VERSION 5.7 ;
  NOWIREEXTENSIONATPIN ON ;
  DIVIDERCHAR "/" ;
  BUSBITCHARS "[]" ;
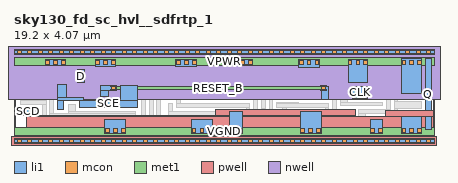
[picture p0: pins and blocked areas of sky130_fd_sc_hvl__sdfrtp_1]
MACRO sky130_fd_sc_hvl__sdfrtp_1
  CLASS BLOCK ;
  FOREIGN sky130_fd_sc_hvl__sdfrtp_1 ;
  ORIGIN 0.000 0.000 ;
  SIZE 19.200 BY 4.070 ;
  PIN CLK
    ANTENNAGATEAREA 0.585000 ;
    PORT
      LAYER li1 ;
        RECT 15.485 1.955 16.140 2.495 ;
    END
  END CLK
  PIN D
    ANTENNAGATEAREA 0.420000 ;
    PORT
      LAYER li1 ;
        RECT 2.910 2.660 3.205 3.260 ;
    END
  END D
  PIN RESET_B
    ANTENNAGATEAREA 1.260000 ;
    PORT
      LAYER li1 ;
        RECT 3.965 2.290 4.675 2.525 ;
        RECT 3.965 2.015 4.300 2.290 ;
        RECT 8.295 2.225 8.760 2.535 ;
        RECT 14.040 1.895 14.370 2.490 ;
      LAYER mcon ;
        RECT 4.475 2.320 4.645 2.490 ;
        RECT 8.315 2.320 8.485 2.490 ;
        RECT 14.075 2.320 14.245 2.490 ;
      LAYER met1 ;
        RECT 4.415 2.475 4.705 2.520 ;
        RECT 8.255 2.475 8.545 2.520 ;
        RECT 14.015 2.475 14.305 2.520 ;
        RECT 4.415 2.335 14.305 2.475 ;
        RECT 4.415 2.290 4.705 2.335 ;
        RECT 8.255 2.290 8.545 2.335 ;
        RECT 14.015 2.290 14.305 2.335 ;
    END
  END RESET_B
  PIN SCD
    ANTENNAGATEAREA 0.420000 ;
    PORT
      LAYER li1 ;
        RECT 0.105 1.180 1.115 1.510 ;
    END
  END SCD
  PIN SCE
    ANTENNAGATEAREA 0.840000 ;
    PORT
      LAYER li1 ;
        RECT 1.995 2.005 2.380 2.575 ;
        RECT 1.995 1.835 3.175 2.005 ;
        RECT 4.880 1.835 5.635 2.525 ;
        RECT 1.995 1.445 2.245 1.835 ;
        RECT 3.005 1.550 5.635 1.835 ;
    END
  END SCE
  PIN VGND
    USE GROUND ;
    PORT
      LAYER li1 ;
        RECT 4.155 0.365 5.105 0.995 ;
        RECT 8.115 0.365 9.065 0.995 ;
        RECT 9.840 0.365 10.430 1.345 ;
        RECT 13.085 0.365 14.035 1.365 ;
        RECT 16.275 0.365 16.865 0.995 ;
        RECT 17.730 0.365 18.640 1.305 ;
      LAYER mcon ;
        RECT 4.185 0.395 4.355 0.565 ;
        RECT 4.545 0.395 4.715 0.565 ;
        RECT 4.905 0.395 5.075 0.565 ;
        RECT 8.145 0.395 8.315 0.565 ;
        RECT 8.505 0.395 8.675 0.565 ;
        RECT 8.865 0.395 9.035 0.565 ;
        RECT 9.870 0.395 10.040 0.565 ;
        RECT 10.230 0.395 10.400 0.565 ;
        RECT 13.115 0.395 13.285 0.565 ;
        RECT 13.475 0.395 13.645 0.565 ;
        RECT 13.835 0.395 14.005 0.565 ;
        RECT 16.305 0.395 16.475 0.565 ;
        RECT 16.665 0.395 16.835 0.565 ;
        RECT 17.740 0.395 17.910 0.565 ;
        RECT 18.100 0.395 18.270 0.565 ;
        RECT 18.460 0.395 18.630 0.565 ;
      LAYER met1 ;
        RECT 0.000 0.255 19.200 0.625 ;
    END
  END VGND
  PIN VNB
    ANTENNADIFFAREA 3.264000 ;
    PORT
      LAYER pwell ;
        RECT 9.215 1.180 15.625 1.455 ;
        RECT 0.555 1.105 15.625 1.180 ;
        RECT 16.995 1.105 19.180 1.415 ;
        RECT 0.555 0.215 19.180 1.105 ;
        RECT -0.130 -0.215 19.330 0.215 ;
      LAYER li1 ;
        RECT 0.000 -0.085 19.200 0.085 ;
      LAYER mcon ;
        RECT 0.155 -0.085 0.325 0.085 ;
        RECT 0.635 -0.085 0.805 0.085 ;
        RECT 1.115 -0.085 1.285 0.085 ;
        RECT 1.595 -0.085 1.765 0.085 ;
        RECT 2.075 -0.085 2.245 0.085 ;
        RECT 2.555 -0.085 2.725 0.085 ;
        RECT 3.035 -0.085 3.205 0.085 ;
        RECT 3.515 -0.085 3.685 0.085 ;
        RECT 3.995 -0.085 4.165 0.085 ;
        RECT 4.475 -0.085 4.645 0.085 ;
        RECT 4.955 -0.085 5.125 0.085 ;
        RECT 5.435 -0.085 5.605 0.085 ;
        RECT 5.915 -0.085 6.085 0.085 ;
        RECT 6.395 -0.085 6.565 0.085 ;
        RECT 6.875 -0.085 7.045 0.085 ;
        RECT 7.355 -0.085 7.525 0.085 ;
        RECT 7.835 -0.085 8.005 0.085 ;
        RECT 8.315 -0.085 8.485 0.085 ;
        RECT 8.795 -0.085 8.965 0.085 ;
        RECT 9.275 -0.085 9.445 0.085 ;
        RECT 9.755 -0.085 9.925 0.085 ;
        RECT 10.235 -0.085 10.405 0.085 ;
        RECT 10.715 -0.085 10.885 0.085 ;
        RECT 11.195 -0.085 11.365 0.085 ;
        RECT 11.675 -0.085 11.845 0.085 ;
        RECT 12.155 -0.085 12.325 0.085 ;
        RECT 12.635 -0.085 12.805 0.085 ;
        RECT 13.115 -0.085 13.285 0.085 ;
        RECT 13.595 -0.085 13.765 0.085 ;
        RECT 14.075 -0.085 14.245 0.085 ;
        RECT 14.555 -0.085 14.725 0.085 ;
        RECT 15.035 -0.085 15.205 0.085 ;
        RECT 15.515 -0.085 15.685 0.085 ;
        RECT 15.995 -0.085 16.165 0.085 ;
        RECT 16.475 -0.085 16.645 0.085 ;
        RECT 16.955 -0.085 17.125 0.085 ;
        RECT 17.435 -0.085 17.605 0.085 ;
        RECT 17.915 -0.085 18.085 0.085 ;
        RECT 18.395 -0.085 18.565 0.085 ;
        RECT 18.875 -0.085 19.045 0.085 ;
      LAYER met1 ;
        RECT 0.000 -0.115 19.200 0.115 ;
    END
  END VNB
  PIN VPB
    ANTENNADIFFAREA 3.264000 ;
    PORT
      LAYER nwell ;
        RECT -0.330 1.885 19.530 4.485 ;
      LAYER li1 ;
        RECT 0.000 3.985 19.200 4.155 ;
      LAYER mcon ;
        RECT 0.155 3.985 0.325 4.155 ;
        RECT 0.635 3.985 0.805 4.155 ;
        RECT 1.115 3.985 1.285 4.155 ;
        RECT 1.595 3.985 1.765 4.155 ;
        RECT 2.075 3.985 2.245 4.155 ;
        RECT 2.555 3.985 2.725 4.155 ;
        RECT 3.035 3.985 3.205 4.155 ;
        RECT 3.515 3.985 3.685 4.155 ;
        RECT 3.995 3.985 4.165 4.155 ;
        RECT 4.475 3.985 4.645 4.155 ;
        RECT 4.955 3.985 5.125 4.155 ;
        RECT 5.435 3.985 5.605 4.155 ;
        RECT 5.915 3.985 6.085 4.155 ;
        RECT 6.395 3.985 6.565 4.155 ;
        RECT 6.875 3.985 7.045 4.155 ;
        RECT 7.355 3.985 7.525 4.155 ;
        RECT 7.835 3.985 8.005 4.155 ;
        RECT 8.315 3.985 8.485 4.155 ;
        RECT 8.795 3.985 8.965 4.155 ;
        RECT 9.275 3.985 9.445 4.155 ;
        RECT 9.755 3.985 9.925 4.155 ;
        RECT 10.235 3.985 10.405 4.155 ;
        RECT 10.715 3.985 10.885 4.155 ;
        RECT 11.195 3.985 11.365 4.155 ;
        RECT 11.675 3.985 11.845 4.155 ;
        RECT 12.155 3.985 12.325 4.155 ;
        RECT 12.635 3.985 12.805 4.155 ;
        RECT 13.115 3.985 13.285 4.155 ;
        RECT 13.595 3.985 13.765 4.155 ;
        RECT 14.075 3.985 14.245 4.155 ;
        RECT 14.555 3.985 14.725 4.155 ;
        RECT 15.035 3.985 15.205 4.155 ;
        RECT 15.515 3.985 15.685 4.155 ;
        RECT 15.995 3.985 16.165 4.155 ;
        RECT 16.475 3.985 16.645 4.155 ;
        RECT 16.955 3.985 17.125 4.155 ;
        RECT 17.435 3.985 17.605 4.155 ;
        RECT 17.915 3.985 18.085 4.155 ;
        RECT 18.395 3.985 18.565 4.155 ;
        RECT 18.875 3.985 19.045 4.155 ;
      LAYER met1 ;
        RECT 0.000 3.955 19.200 4.185 ;
    END
  END VPB
  PIN VPWR
    USE POWER ;
    PORT
      LAYER li1 ;
        RECT 1.420 3.455 2.370 3.705 ;
        RECT 3.735 3.405 4.625 3.705 ;
        RECT 7.405 3.415 8.355 3.705 ;
        RECT 9.965 3.485 10.915 3.735 ;
        RECT 13.015 3.370 13.965 3.705 ;
        RECT 15.275 2.675 16.165 3.705 ;
        RECT 17.730 2.175 18.640 3.755 ;
      LAYER mcon ;
        RECT 1.450 3.505 1.620 3.675 ;
        RECT 1.810 3.505 1.980 3.675 ;
        RECT 2.170 3.505 2.340 3.675 ;
        RECT 3.735 3.505 3.905 3.675 ;
        RECT 4.095 3.505 4.265 3.675 ;
        RECT 4.455 3.505 4.625 3.675 ;
        RECT 7.435 3.505 7.605 3.675 ;
        RECT 7.795 3.505 7.965 3.675 ;
        RECT 8.155 3.505 8.325 3.675 ;
        RECT 9.995 3.515 10.165 3.685 ;
        RECT 10.355 3.515 10.525 3.685 ;
        RECT 10.715 3.515 10.885 3.685 ;
        RECT 13.045 3.505 13.215 3.675 ;
        RECT 13.405 3.505 13.575 3.675 ;
        RECT 13.765 3.505 13.935 3.675 ;
        RECT 15.275 3.505 15.445 3.675 ;
        RECT 15.635 3.505 15.805 3.675 ;
        RECT 15.995 3.505 16.165 3.675 ;
        RECT 17.740 3.505 17.910 3.675 ;
        RECT 18.100 3.505 18.270 3.675 ;
        RECT 18.460 3.505 18.630 3.675 ;
      LAYER met1 ;
        RECT 0.000 3.445 19.200 3.815 ;
    END
  END VPWR
  PIN Q
    ANTENNADIFFAREA 0.626250 ;
    PORT
      LAYER li1 ;
        RECT 18.820 0.515 19.075 3.755 ;
    END
  END Q
  OBS
      LAYER li1 ;
        RECT 0.305 3.275 0.635 3.705 ;
        RECT 2.560 3.535 3.555 3.705 ;
        RECT 2.560 3.275 2.730 3.535 ;
        RECT 0.305 3.105 2.730 3.275 ;
        RECT 3.385 3.225 3.555 3.535 ;
        RECT 4.805 3.635 6.005 3.805 ;
        RECT 4.805 3.225 4.975 3.635 ;
        RECT 0.305 1.860 0.475 3.105 ;
        RECT 3.385 3.055 4.975 3.225 ;
        RECT 0.730 2.755 2.730 2.925 ;
        RECT 5.155 2.875 5.485 3.455 ;
        RECT 5.755 3.165 6.005 3.635 ;
        RECT 0.730 2.255 1.060 2.755 ;
        RECT 0.305 1.690 1.465 1.860 ;
        RECT 0.665 0.435 0.995 0.995 ;
        RECT 1.295 0.915 1.465 1.690 ;
        RECT 1.645 1.265 1.815 2.755 ;
        RECT 2.560 2.480 2.730 2.755 ;
        RECT 3.385 2.705 5.485 2.875 ;
        RECT 3.385 2.480 3.555 2.705 ;
        RECT 2.560 2.310 3.555 2.480 ;
        RECT 2.480 1.345 2.810 1.655 ;
        RECT 2.480 1.265 5.535 1.345 ;
        RECT 1.645 1.175 5.535 1.265 ;
        RECT 1.645 1.095 2.810 1.175 ;
        RECT 1.295 0.615 2.485 0.915 ;
        RECT 3.645 0.435 3.975 0.995 ;
        RECT 5.285 0.515 5.535 1.175 ;
        RECT 5.835 1.005 6.005 3.165 ;
        RECT 5.755 0.515 6.005 1.005 ;
        RECT 6.185 3.635 7.215 3.805 ;
        RECT 0.665 0.265 3.975 0.435 ;
        RECT 6.185 0.435 6.355 3.635 ;
        RECT 6.535 2.885 6.865 3.455 ;
        RECT 7.045 3.235 7.215 3.635 ;
        RECT 8.535 3.635 9.785 3.805 ;
        RECT 8.535 3.235 8.705 3.635 ;
        RECT 7.045 3.065 8.705 3.235 ;
        RECT 8.885 2.885 9.215 3.455 ;
        RECT 6.535 2.715 9.215 2.885 ;
        RECT 6.535 0.995 6.705 2.715 ;
        RECT 6.950 2.085 7.280 2.535 ;
        RECT 6.950 1.915 7.605 2.085 ;
        RECT 7.045 1.345 7.255 1.735 ;
        RECT 7.435 1.695 7.605 1.915 ;
        RECT 7.785 2.045 8.115 2.535 ;
        RECT 9.045 2.395 9.215 2.715 ;
        RECT 9.455 3.305 9.785 3.635 ;
        RECT 14.145 3.355 15.095 3.525 ;
        RECT 9.455 3.135 12.810 3.305 ;
        RECT 14.145 3.190 14.315 3.355 ;
        RECT 9.455 2.695 9.785 3.135 ;
        RECT 10.960 2.675 11.440 2.955 ;
        RECT 10.490 2.395 10.780 2.555 ;
        RECT 9.045 2.225 10.780 2.395 ;
        RECT 10.960 2.045 11.130 2.675 ;
        RECT 11.620 2.455 11.790 3.135 ;
        RECT 7.785 1.875 11.130 2.045 ;
        RECT 7.435 1.525 10.780 1.695 ;
        RECT 7.045 1.175 9.635 1.345 ;
        RECT 6.535 0.615 6.865 0.995 ;
        RECT 7.045 0.435 7.255 1.175 ;
        RECT 9.305 0.885 9.635 1.175 ;
        RECT 6.185 0.265 7.255 0.435 ;
        RECT 10.610 0.435 10.780 1.525 ;
        RECT 10.960 1.285 11.130 1.875 ;
        RECT 11.310 2.285 11.790 2.455 ;
        RECT 11.310 1.465 11.480 2.285 ;
        RECT 11.970 2.105 12.300 2.955 ;
        RECT 12.480 2.285 12.810 3.135 ;
        RECT 13.030 3.020 14.315 3.190 ;
        RECT 13.030 2.105 13.200 3.020 ;
        RECT 14.495 2.840 14.745 3.175 ;
        RECT 11.660 1.935 13.200 2.105 ;
        RECT 13.380 2.670 14.745 2.840 ;
        RECT 11.660 1.365 11.830 1.935 ;
        RECT 13.380 1.895 13.710 2.670 ;
        RECT 12.010 1.715 13.020 1.755 ;
        RECT 12.010 1.545 14.395 1.715 ;
        RECT 10.960 0.615 11.325 1.285 ;
        RECT 11.660 0.615 12.105 1.365 ;
        RECT 12.285 0.435 12.455 1.545 ;
        RECT 14.225 0.705 14.395 1.545 ;
        RECT 14.575 1.345 14.745 2.670 ;
        RECT 14.925 2.275 15.095 3.355 ;
        RECT 14.925 1.775 15.255 2.275 ;
        RECT 16.345 2.125 16.595 3.505 ;
        RECT 17.065 2.305 17.550 3.005 ;
        RECT 16.345 1.955 17.200 2.125 ;
        RECT 14.925 1.605 16.850 1.775 ;
        RECT 17.030 1.425 17.200 1.955 ;
        RECT 14.575 1.175 15.535 1.345 ;
        RECT 15.205 0.885 15.535 1.175 ;
        RECT 15.755 1.255 17.200 1.425 ;
        RECT 17.380 1.815 17.550 2.305 ;
        RECT 17.380 1.485 18.615 1.815 ;
        RECT 15.755 0.705 16.085 1.255 ;
        RECT 17.380 1.075 17.550 1.485 ;
        RECT 17.105 0.825 17.550 1.075 ;
        RECT 14.225 0.535 16.085 0.705 ;
        RECT 10.610 0.265 12.455 0.435 ;
  END
END sky130_fd_sc_hvl__sdfrtp_1
END LIBRARY

